One B-rep face of a CAD part: STEP entity #109.
In plain terms, the planar face has unit normal (0, -1, 0).
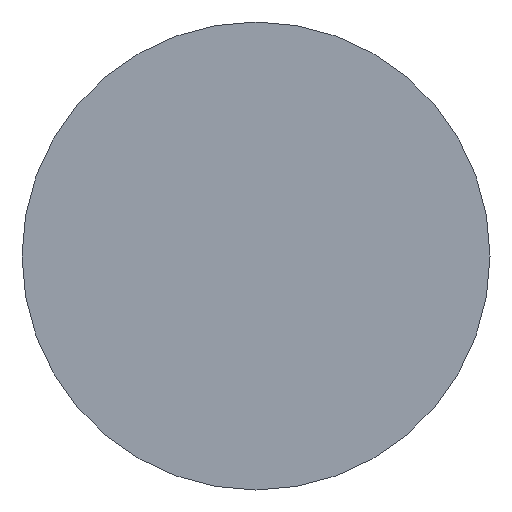
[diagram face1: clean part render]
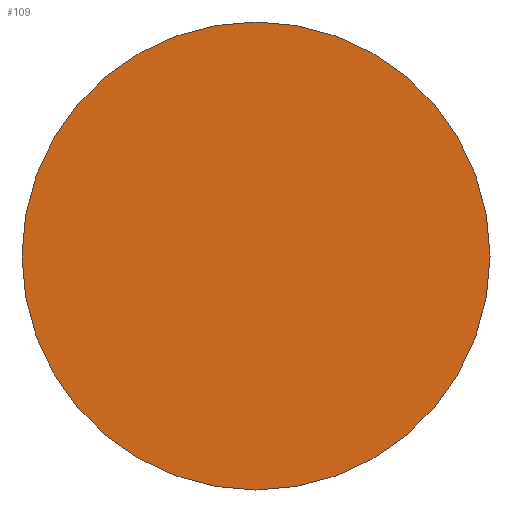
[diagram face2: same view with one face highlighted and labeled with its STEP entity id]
Its self-contained STEP definition (entity closure, numbers rounded to 3 decimals):
#24 = VERTEX_POINT('',#25);
#25 = CARTESIAN_POINT('',(50.,-60.,0.));
#32 = CYLINDRICAL_SURFACE('',#33,50.);
#33 = AXIS2_PLACEMENT_3D('',#34,#35,#36);
#34 = CARTESIAN_POINT('',(0.,0.,0.));
#35 = DIRECTION('',(-0.,1.,-0.));
#36 = DIRECTION('',(1.,0.,0.));
#51 = EDGE_CURVE('',#24,#24,#52,.T.);
#52 = SURFACE_CURVE('',#53,(#58,#65),.PCURVE_S1.);
#53 = CIRCLE('',#54,50.);
#54 = AXIS2_PLACEMENT_3D('',#55,#56,#57);
#55 = CARTESIAN_POINT('',(0.,-60.,0.));
#56 = DIRECTION('',(0.,-1.,0.));
#57 = DIRECTION('',(1.,0.,0.));
#58 = PCURVE('',#32,#59);
#59 = DEFINITIONAL_REPRESENTATION('',(#60),#64);
#60 = LINE('',#61,#62);
#61 = CARTESIAN_POINT('',(-0.,-60.));
#62 = VECTOR('',#63,1.);
#63 = DIRECTION('',(-1.,0.));
#64 = ( GEOMETRIC_REPRESENTATION_CONTEXT(2) 
PARAMETRIC_REPRESENTATION_CONTEXT() REPRESENTATION_CONTEXT('2D SPACE',''
  ) );
#65 = PCURVE('',#66,#71);
#66 = PLANE('',#67);
#67 = AXIS2_PLACEMENT_3D('',#68,#69,#70);
#68 = CARTESIAN_POINT('',(0.,-60.,0.));
#69 = DIRECTION('',(-0.,-1.,-0.));
#70 = DIRECTION('',(0.,0.,-1.));
#71 = DEFINITIONAL_REPRESENTATION('',(#72),#76);
#72 = CIRCLE('',#73,50.);
#73 = AXIS2_PLACEMENT_2D('',#74,#75);
#74 = CARTESIAN_POINT('',(0.,0.));
#75 = DIRECTION('',(0.,1.));
#76 = ( GEOMETRIC_REPRESENTATION_CONTEXT(2) 
PARAMETRIC_REPRESENTATION_CONTEXT() REPRESENTATION_CONTEXT('2D SPACE',''
  ) );
#109 = ADVANCED_FACE('',(#110),#66,.T.);
#110 = FACE_BOUND('',#111,.T.);
#111 = EDGE_LOOP('',(#112));
#112 = ORIENTED_EDGE('',*,*,#51,.T.);
